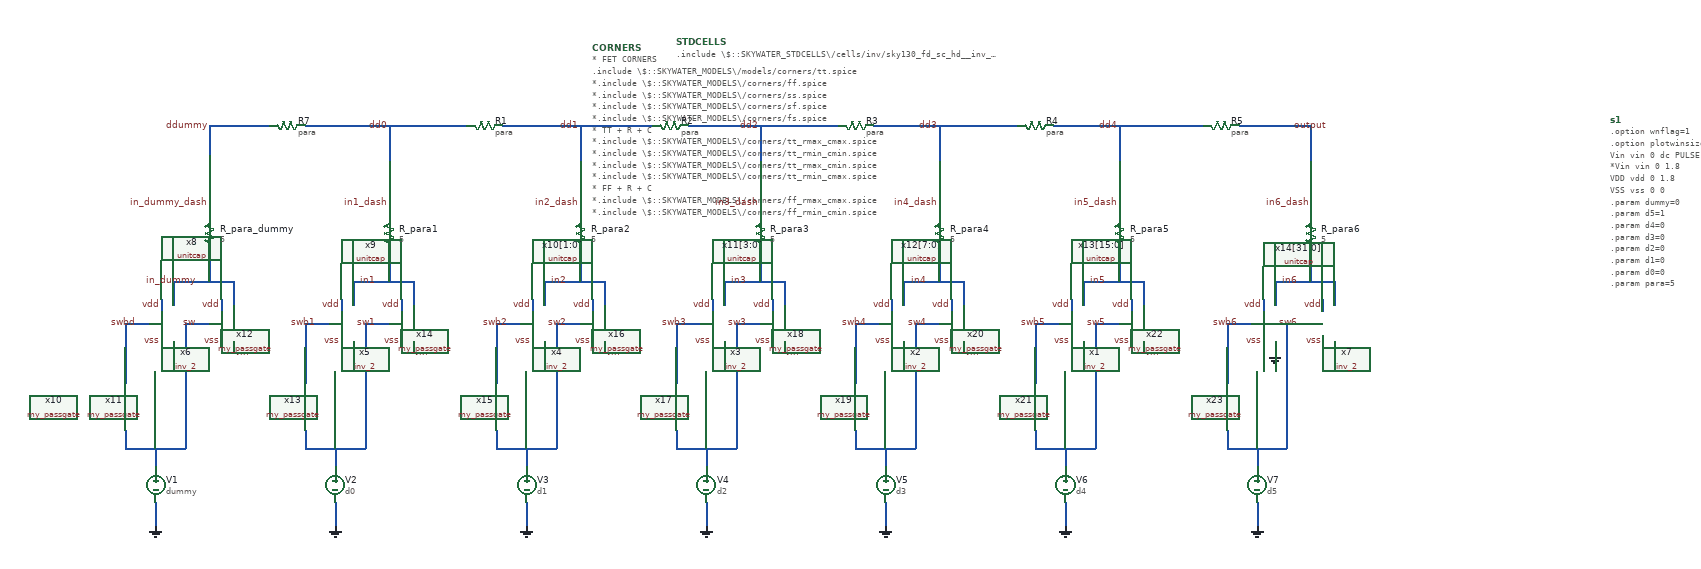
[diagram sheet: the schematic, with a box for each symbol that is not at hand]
v {xschem version=3.0.0 file_version=1.2 }
G {}
K {}
V {}
S {}
E {}
N 120 -60 120 -30 {
lab=sw}
N 120 -30 220 -30 {
lab=sw}
N 220 -170 220 -30 {
lab=sw}
N 120 -170 120 -140 {
lab=swbd}
N 200 -210 200 -190 {
lab=GND}
N 240 -240 260 -240 {
lab=sw}
N 140 -240 160 -240 {
lab=swbd}
N 220 -240 220 -170 {
lab=sw}
N 220 -240 240 -240 {
lab=sw}
N 120 -240 140 -240 {
lab=swbd}
N 120 -240 120 -170 {
lab=swbd}
N 300 -210 300 -190 {
lab=vin}
N 170 60 170 100 {
lab=GND}
N 170 -30 170 0 {
lab=sw}
N 200 -310 200 -270 {
lab=in_dummy}
N 200 -310 300 -310 {
lab=in_dummy}
N 300 -310 300 -270 {
lab=in_dummy}
N 420 -60 420 -30 {
lab=sw1}
N 420 -30 520 -30 {
lab=sw1}
N 520 -170 520 -30 {
lab=sw1}
N 420 -170 420 -140 {
lab=swb1}
N 500 -210 500 -190 {
lab=GND}
N 540 -240 560 -240 {
lab=sw1}
N 440 -240 460 -240 {
lab=swb1}
N 520 -240 520 -170 {
lab=sw1}
N 520 -240 540 -240 {
lab=sw1}
N 420 -240 440 -240 {
lab=swb1}
N 420 -240 420 -170 {
lab=swb1}
N 600 -210 600 -190 {
lab=vin}
N 470 60 470 100 {
lab=GND}
N 470 -30 470 0 {
lab=sw1}
N 500 -310 500 -270 {
lab=in1}
N 500 -310 600 -310 {
lab=in1}
N 600 -310 600 -270 {
lab=in1}
N 560 -450 560 -420 {
lab=in1_dash}
N 560 -570 560 -510 {
lab=d0}
N 740 -60 740 -30 {
lab=sw2}
N 740 -30 840 -30 {
lab=sw2}
N 840 -170 840 -30 {
lab=sw2}
N 740 -170 740 -140 {
lab=swb2}
N 820 -210 820 -190 {
lab=GND}
N 860 -240 880 -240 {
lab=sw2}
N 760 -240 780 -240 {
lab=swb2}
N 840 -240 840 -170 {
lab=sw2}
N 840 -240 860 -240 {
lab=sw2}
N 740 -240 760 -240 {
lab=swb2}
N 740 -240 740 -170 {
lab=swb2}
N 920 -210 920 -190 {
lab=vin}
N 790 60 790 100 {
lab=GND}
N 790 -30 790 0 {
lab=sw2}
N 820 -310 820 -270 {
lab=in2}
N 820 -310 920 -310 {
lab=in2}
N 920 -310 920 -270 {
lab=in2}
N 880 -450 880 -420 {
lab=in2_dash}
N 880 -570 880 -510 {
lab=dd1}
N 1040 -60 1040 -30 {
lab=sw3}
N 1040 -30 1140 -30 {
lab=sw3}
N 1140 -170 1140 -30 {
lab=sw3}
N 1040 -170 1040 -140 {
lab=swb3}
N 1120 -210 1120 -190 {
lab=GND}
N 1160 -240 1180 -240 {
lab=sw3}
N 1060 -240 1080 -240 {
lab=swb3}
N 1140 -240 1140 -170 {
lab=sw3}
N 1140 -240 1160 -240 {
lab=sw3}
N 1040 -240 1060 -240 {
lab=swb3}
N 1040 -240 1040 -170 {
lab=swb3}
N 1220 -210 1220 -190 {
lab=vin}
N 1090 60 1090 100 {
lab=GND}
N 1090 -30 1090 0 {
lab=sw3}
N 1120 -310 1120 -270 {
lab=in3}
N 1120 -310 1220 -310 {
lab=in3}
N 1220 -310 1220 -270 {
lab=in3}
N 1180 -450 1180 -420 {
lab=in3_dash}
N 1180 -570 1180 -510 {
lab=dd2}
N 1340 -60 1340 -30 {
lab=sw4}
N 1340 -30 1440 -30 {
lab=sw4}
N 1440 -170 1440 -30 {
lab=sw4}
N 1340 -170 1340 -140 {
lab=swb4}
N 1420 -210 1420 -190 {
lab=GND}
N 1460 -240 1480 -240 {
lab=sw4}
N 1360 -240 1380 -240 {
lab=swb4}
N 1440 -240 1440 -170 {
lab=sw4}
N 1440 -240 1460 -240 {
lab=sw4}
N 1340 -240 1360 -240 {
lab=swb4}
N 1340 -240 1340 -170 {
lab=swb4}
N 1520 -210 1520 -190 {
lab=vin}
N 1390 60 1390 100 {
lab=GND}
N 1390 -30 1390 0 {
lab=sw4}
N 1420 -310 1420 -270 {
lab=in4}
N 1420 -310 1520 -310 {
lab=in4}
N 1520 -310 1520 -270 {
lab=in4}
N 1480 -450 1480 -420 {
lab=in4_dash}
N 1480 -570 1480 -510 {
lab=dd3}
N 1640 -60 1640 -30 {
lab=sw5}
N 1640 -30 1740 -30 {
lab=sw5}
N 1740 -170 1740 -30 {
lab=sw5}
N 1640 -170 1640 -140 {
lab=swb5}
N 1720 -210 1720 -190 {
lab=GND}
N 1760 -240 1780 -240 {
lab=sw5}
N 1660 -240 1680 -240 {
lab=swb5}
N 1740 -240 1740 -170 {
lab=sw5}
N 1740 -240 1760 -240 {
lab=sw5}
N 1640 -240 1660 -240 {
lab=swb5}
N 1640 -240 1640 -170 {
lab=swb5}
N 1820 -210 1820 -190 {
lab=vin}
N 1690 60 1690 100 {
lab=GND}
N 1690 -30 1690 0 {
lab=sw5}
N 1720 -310 1720 -270 {
lab=in5}
N 1720 -310 1820 -310 {
lab=in5}
N 1820 -310 1820 -270 {
lab=in5}
N 1780 -450 1780 -420 {
lab=in5_dash}
N 1780 -570 1780 -510 {
lab=dd4}
N 1960 -60 1960 -30 {
lab=sw6}
N 1960 -30 2060 -30 {
lab=sw6}
N 2060 -170 2060 -30 {
lab=sw6}
N 1960 -170 1960 -140 {
lab=swb6}
N 2040 -210 2040 -190 {
lab=GND}
N 2080 -240 2100 -240 {
lab=sw6}
N 1980 -240 2000 -240 {
lab=swb6}
N 2060 -240 2060 -170 {
lab=sw6}
N 2060 -240 2080 -240 {
lab=sw6}
N 1960 -240 1980 -240 {
lab=swb6}
N 1960 -240 1960 -170 {
lab=swb6}
N 2140 -210 2140 -190 {
lab=vin}
N 2010 60 2010 100 {
lab=GND}
N 2010 -30 2010 0 {
lab=sw6}
N 2040 -310 2040 -270 {
lab=in6}
N 2040 -310 2140 -310 {
lab=in6}
N 2140 -310 2140 -270 {
lab=in6}
N 2100 -450 2100 -420 {
lab=in6_dash}
N 2100 -570 2100 -510 {
lab=output}
N 180 -220 180 -200 {
lab=vss}
N 180 -280 180 -260 {
lab=vdd}
N 280 -220 280 -200 {
lab=vss}
N 280 -280 280 -260 {
lab=vdd}
N 480 -220 480 -200 {
lab=vss}
N 480 -280 480 -260 {
lab=vdd}
N 580 -220 580 -200 {
lab=vss}
N 580 -280 580 -260 {
lab=vdd}
N 800 -220 800 -200 {
lab=vss}
N 800 -280 800 -260 {
lab=vdd}
N 900 -220 900 -200 {
lab=vss}
N 900 -280 900 -260 {
lab=vdd}
N 1100 -220 1100 -200 {
lab=vss}
N 1100 -280 1100 -260 {
lab=vdd}
N 1200 -220 1200 -200 {
lab=vss}
N 1200 -280 1200 -260 {
lab=vdd}
N 1400 -220 1400 -200 {
lab=vss}
N 1400 -280 1400 -260 {
lab=vdd}
N 1500 -220 1500 -200 {
lab=vss}
N 1500 -280 1500 -260 {
lab=vdd}
N 1700 -220 1700 -200 {
lab=vss}
N 1700 -280 1700 -260 {
lab=vdd}
N 1800 -220 1800 -200 {
lab=vss}
N 1800 -280 1800 -260 {
lab=vdd}
N 2020 -220 2020 -200 {
lab=vss}
N 2020 -280 2020 -260 {
lab=vdd}
N 2120 -220 2120 -200 {
lab=vss}
N 2120 -280 2120 -260 {
lab=vdd}
N 260 -570 260 -520 {
lab=ddummy}
N 260 -460 260 -420 {
lab=in_dummy_dash}
N 260 -570 360 -570 {
lab=ddummy}
N 420 -570 690 -570 {
lab=d0}
N 750 -570 1000 -570 {
lab=dd1}
N 1060 -570 1310 -570 {
lab=dd2}
N 1370 -570 1610 -570 {
lab=dd3}
N 1670 -570 1920 -570 {
lab=dd4}
N 1980 -570 2020 -570 {
lab=output}
N 2020 -570 2100 -570 {
lab=output}
N 260 -360 260 -310 {
lab=in_dummy}
N 560 -360 560 -310 {
lab=in1}
N 880 -360 880 -310 {
lab=in2}
N 1180 -360 1180 -310 {
lab=in3}
N 1480 -360 1480 -310 {
lab=in4}
N 1780 -360 1780 -310 {
lab=in5}
N 2100 -360 2100 -310 {
lab=in6}
C {gnd.sym} 200 -190 0 0 {name=l2 lab=GND}
C {lab_wire.sym} 240 -240 0 0 {name=l3 sig_type=std_logic lab=sw}
C {lab_wire.sym} 140 -240 0 0 {name=l4 sig_type=std_logic lab=swbd
}
C {vsource.sym} 170 30 0 0 {name=V1 value=dummy
}
C {gnd.sym} 170 100 0 0 {name=l7 lab=GND}
C {lab_wire.sym} 300 -190 2 0 {name=l6 sig_type=std_logic lab=vin
}
C {gnd.sym} 500 -190 0 0 {name=l9 lab=GND}
C {lab_wire.sym} 540 -240 0 0 {name=l10 sig_type=std_logic lab=sw1}
C {lab_wire.sym} 440 -240 0 0 {name=l11 sig_type=std_logic lab=swb1
}
C {vsource.sym} 470 30 0 0 {name=V2 value=d0}
C {gnd.sym} 470 100 0 0 {name=l13 lab=GND}
C {lab_wire.sym} 600 -190 2 0 {name=l14 sig_type=std_logic lab=vin
}
C {gnd.sym} 820 -190 0 0 {name=l16 lab=GND}
C {lab_wire.sym} 860 -240 0 0 {name=l17 sig_type=std_logic lab=sw2}
C {lab_wire.sym} 760 -240 0 0 {name=l18 sig_type=std_logic lab=swb2
}
C {vsource.sym} 790 30 0 0 {name=V3 value=d1
}
C {gnd.sym} 790 100 0 0 {name=l20 lab=GND}
C {lab_wire.sym} 920 -190 2 0 {name=l21 sig_type=std_logic lab=vin
}
C {gnd.sym} 1120 -190 0 0 {name=l23 lab=GND}
C {lab_wire.sym} 1160 -240 0 0 {name=l24 sig_type=std_logic lab=sw3}
C {lab_wire.sym} 1060 -240 0 0 {name=l25 sig_type=std_logic lab=swb3
}
C {vsource.sym} 1090 30 0 0 {name=V4 value=d2}
C {gnd.sym} 1090 100 0 0 {name=l27 lab=GND}
C {lab_wire.sym} 1220 -190 2 0 {name=l28 sig_type=std_logic lab=vin
}
C {gnd.sym} 1420 -190 0 0 {name=l30 lab=GND}
C {lab_wire.sym} 1460 -240 0 0 {name=l31 sig_type=std_logic lab=sw4}
C {lab_wire.sym} 1360 -240 0 0 {name=l32 sig_type=std_logic lab=swb4
}
C {vsource.sym} 1390 30 0 0 {name=V5 value=d3
}
C {gnd.sym} 1390 100 0 0 {name=l34 lab=GND}
C {lab_wire.sym} 1520 -190 2 0 {name=l35 sig_type=std_logic lab=vin
}
C {gnd.sym} 1720 -190 0 0 {name=l37 lab=GND}
C {lab_wire.sym} 1760 -240 0 0 {name=l38 sig_type=std_logic lab=sw5}
C {lab_wire.sym} 1660 -240 0 0 {name=l39 sig_type=std_logic lab=swb5
}
C {vsource.sym} 1690 30 0 0 {name=V6 value=d4
}
C {gnd.sym} 1690 100 0 0 {name=l41 lab=GND}
C {lab_wire.sym} 1820 -190 2 0 {name=l42 sig_type=std_logic lab=vin
}
C {gnd.sym} 2040 -190 0 0 {name=l44 lab=GND}
C {lab_wire.sym} 2080 -240 0 0 {name=l45 sig_type=std_logic lab=sw6}
C {lab_wire.sym} 1980 -240 0 0 {name=l46 sig_type=std_logic lab=swb6
}
C {vsource.sym} 2010 30 0 0 {name=V7 value=d5
}
C {gnd.sym} 2010 100 0 0 {name=l48 lab=GND}
C {lab_wire.sym} 2140 -190 2 0 {name=l49 sig_type=std_logic lab=vin
}
C {devices/code.sym} 900 -700 0 0 {
name=CORNERS 
only_toplevel=true 
format="tcleval( @value )"
spice_ignore="tcleval($cmdline_ignore)"
value="* FET CORNERS
.include \\\\$::SKYWATER_MODELS\\\\/models/corners/tt.spice
*.include \\\\$::SKYWATER_MODELS\\\\/corners/ff.spice
*.include \\\\$::SKYWATER_MODELS\\\\/corners/ss.spice
*.include \\\\$::SKYWATER_MODELS\\\\/corners/sf.spice
*.include \\\\$::SKYWATER_MODELS\\\\/corners/fs.spice

* TT + R + C
*.include \\\\$::SKYWATER_MODELS\\\\/corners/tt_rmax_cmax.spice
*.include \\\\$::SKYWATER_MODELS\\\\/corners/tt_rmin_cmin.spice
*.include \\\\$::SKYWATER_MODELS\\\\/corners/tt_rmax_cmin.spice
*.include \\\\$::SKYWATER_MODELS\\\\/corners/tt_rmin_cmax.spice

* FF + R + C
*.include \\\\$::SKYWATER_MODELS\\\\/corners/ff_rmax_cmax.spice
*.include \\\\$::SKYWATER_MODELS\\\\/corners/ff_rmin_cmin.spice
*.include \\\\$::SKYWATER_MODELS\\\\/corners/ff_rmax_cmin.spice
*.include \\\\$::SKYWATER_MODELS\\\\/corners/ff_rmin_cmax.spice


* SS + R + C
*.include \\\\$::SKYWATER_MODELS\\\\/corners/ss_rmax_cmax.spice
*.include \\\\$::SKYWATER_MODELS\\\\/corners/ss_rmin_cmin.spice
*.include \\\\$::SKYWATER_MODELS\\\\/corners/ss_rmax_cmin.spice
*.include \\\\$::SKYWATER_MODELS\\\\/corners/ss_rmin_cmax.spice

* SF + R + C
*.include \\\\$::SKYWATER_MODELS\\\\/corners/sf_rmax_cmax.spice
*.include \\\\$::SKYWATER_MODELS\\\\/corners/sf_rmin_cmin.spice
*.include \\\\$::SKYWATER_MODELS\\\\/corners/sf_rmax_cmin.spice
*.include \\\\$::SKYWATER_MODELS\\\\/corners/sf_rmin_cmax.spice

* FS + R + C
*.include \\\\$::SKYWATER_MODELS\\\\/corners/fs_rmax_cmax.spice
*.include \\\\$::SKYWATER_MODELS\\\\/corners/fs_rmin_cmin.spice
*.include \\\\$::SKYWATER_MODELS\\\\/corners/fs_rmax_cmin.spice
*.include \\\\$::SKYWATER_MODELS\\\\/corners/fs_rmin_cmax.spice
"}
C {code_shown.sym} 2600 -580 0 0 {name=s1 only_toplevel=false value="
.option wnflag=1
.option plotwinsize=0
Vin vin 0 dc PULSE(0 1 0 12.8u 0 0.2u 13u)
*Vin vin 0 1.8
VDD vdd 0 1.8
VSS vss 0 0

.param dummy=0
.param d5=1
.param d4=0
.param d3=0
.param d2=0
.param d1=0
.param d0=0
.param para=5

.control
save all
tran 1u 13u

meas tran output find v(d5) at=13u

wrdata out output
print output
.endc
"}
C {devices/code.sym} 1040 -710 0 0 {
name=STDCELLS 
only_toplevel=false 
format="tcleval( @value )"
value="

.include \\\\$::SKYWATER_STDCELLS\\\\/cells/inv/sky130_fd_sc_hd__inv_2.spice"
}
C {sar_10b/unitcap/unitcap.sym} 540 -440 0 0 {name=x9}
C {sar_10b/unitcap/unitcap.sym} 860 -440 0 0 {name=x10[1:0]}
C {sar_10b/unitcap/unitcap.sym} 1160 -440 0 0 {name=x11[3:0]}
C {sar_10b/unitcap/unitcap.sym} 1460 -440 0 0 {name=x12[7:0]}
C {sar_10b/unitcap/unitcap.sym} 1760 -440 0 0 {name=x13[15:0]}
C {sar_10b/unitcap/unitcap.sym} 2080 -440 0 0 {name=x14[31:0]}
C {switches/my_passgate.sym} 0 -100 0 0 {name=x10}
C {lab_wire.sym} 180 -210 0 0 {name=l1 sig_type=std_logic lab=vss}
C {lab_wire.sym} 180 -270 0 0 {name=l51 sig_type=std_logic lab=vdd}
C {switches/my_passgate.sym} 100 -100 0 0 {name=x11}
C {lab_wire.sym} 280 -210 0 0 {name=l5 sig_type=std_logic lab=vss}
C {lab_wire.sym} 280 -270 0 0 {name=l8 sig_type=std_logic lab=vdd}
C {switches/my_passgate.sym} 300 -100 0 0 {name=x12}
C {lab_wire.sym} 480 -210 0 0 {name=l12 sig_type=std_logic lab=vss}
C {lab_wire.sym} 480 -270 0 0 {name=l15 sig_type=std_logic lab=vdd}
C {switches/my_passgate.sym} 400 -100 0 0 {name=x13}
C {lab_wire.sym} 580 -210 0 0 {name=l19 sig_type=std_logic lab=vss}
C {lab_wire.sym} 580 -270 0 0 {name=l22 sig_type=std_logic lab=vdd}
C {switches/my_passgate.sym} 620 -100 0 0 {name=x14}
C {lab_wire.sym} 800 -210 0 0 {name=l26 sig_type=std_logic lab=vss}
C {lab_wire.sym} 800 -270 0 0 {name=l29 sig_type=std_logic lab=vdd}
C {switches/my_passgate.sym} 720 -100 0 0 {name=x15}
C {lab_wire.sym} 900 -210 0 0 {name=l33 sig_type=std_logic lab=vss}
C {lab_wire.sym} 900 -270 0 0 {name=l36 sig_type=std_logic lab=vdd}
C {switches/my_passgate.sym} 920 -100 0 0 {name=x16}
C {lab_wire.sym} 1100 -210 0 0 {name=l40 sig_type=std_logic lab=vss}
C {lab_wire.sym} 1100 -270 0 0 {name=l43 sig_type=std_logic lab=vdd}
C {switches/my_passgate.sym} 1020 -100 0 0 {name=x17}
C {lab_wire.sym} 1200 -210 0 0 {name=l47 sig_type=std_logic lab=vss}
C {lab_wire.sym} 1200 -270 0 0 {name=l52 sig_type=std_logic lab=vdd}
C {switches/my_passgate.sym} 1220 -100 0 0 {name=x18}
C {lab_wire.sym} 1400 -210 0 0 {name=l53 sig_type=std_logic lab=vss}
C {lab_wire.sym} 1400 -270 0 0 {name=l54 sig_type=std_logic lab=vdd}
C {switches/my_passgate.sym} 1320 -100 0 0 {name=x19}
C {lab_wire.sym} 1500 -210 0 0 {name=l55 sig_type=std_logic lab=vss}
C {lab_wire.sym} 1500 -270 0 0 {name=l56 sig_type=std_logic lab=vdd}
C {switches/my_passgate.sym} 1520 -100 0 0 {name=x20}
C {lab_wire.sym} 1700 -210 0 0 {name=l57 sig_type=std_logic lab=vss}
C {lab_wire.sym} 1700 -270 0 0 {name=l58 sig_type=std_logic lab=vdd}
C {switches/my_passgate.sym} 1620 -100 0 0 {name=x21}
C {lab_wire.sym} 1800 -210 0 0 {name=l59 sig_type=std_logic lab=vss}
C {lab_wire.sym} 1800 -270 0 0 {name=l60 sig_type=std_logic lab=vdd}
C {switches/my_passgate.sym} 1840 -100 0 0 {name=x22}
C {lab_wire.sym} 2020 -210 0 0 {name=l61 sig_type=std_logic lab=vss}
C {lab_wire.sym} 2020 -270 0 0 {name=l62 sig_type=std_logic lab=vdd}
C {switches/my_passgate.sym} 1940 -100 0 0 {name=x23}
C {lab_wire.sym} 2120 -210 0 0 {name=l63 sig_type=std_logic lab=vss}
C {lab_wire.sym} 2120 -270 0 0 {name=l64 sig_type=std_logic lab=vdd}
C {lab_wire.sym} 2070 -570 0 1 {name=l65 sig_type=std_logic lab=output}
C {xschem_sky130/sky130_stdcells/inv_2.sym} 1960 -100 3 0 {name=x7 VGND=vss VNB=vss VPB=vdd VPWR=vdd prefix=sky130_fd_sc_hd__ }
C {xschem_sky130/sky130_stdcells/inv_2.sym} 1640 -100 3 0 {name=x1 VGND=vss VNB=vss VPB=vdd VPWR=vdd prefix=sky130_fd_sc_hd__ }
C {xschem_sky130/sky130_stdcells/inv_2.sym} 1340 -100 3 0 {name=x2 VGND=vss VNB=vss VPB=vdd VPWR=vdd prefix=sky130_fd_sc_hd__ }
C {xschem_sky130/sky130_stdcells/inv_2.sym} 1040 -100 3 0 {name=x3 VGND=vss VNB=vss VPB=vdd VPWR=vdd prefix=sky130_fd_sc_hd__ }
C {xschem_sky130/sky130_stdcells/inv_2.sym} 740 -100 3 0 {name=x4 VGND=vss VNB=vss VPB=vdd VPWR=vdd prefix=sky130_fd_sc_hd__ }
C {xschem_sky130/sky130_stdcells/inv_2.sym} 420 -100 3 0 {name=x5 VGND=vss VNB=vss VPB=vdd VPWR=vdd prefix=sky130_fd_sc_hd__ }
C {xschem_sky130/sky130_stdcells/inv_2.sym} 120 -100 3 0 {name=x6 VGND=vss VNB=vss VPB=vdd VPWR=vdd prefix=sky130_fd_sc_hd__ }
C {sar_10b/unitcap/unitcap.sym} 240 -450 0 0 {name=x8}
C {res.sym} 390 -570 1 0 {name=R7
value=para
footprint=1206
device=resistor
m=1}
C {res.sym} 720 -570 1 0 {name=R1
value=para
footprint=1206
device=resistor
m=1}
C {res.sym} 1030 -570 1 0 {name=R2
value=para
footprint=1206
device=resistor
m=1}
C {res.sym} 1340 -570 1 0 {name=R3
value=para
footprint=1206
device=resistor
m=1}
C {res.sym} 1640 -570 1 0 {name=R4
value=para
footprint=1206
device=resistor
m=1}
C {res.sym} 1950 -570 1 0 {name=R5
value=para
footprint=1206
device=resistor
m=1}
C {lab_wire.sym} 540 -310 0 0 {name=l66 sig_type=std_logic lab=in1}
C {lab_wire.sym} 860 -310 0 0 {name=l67 sig_type=std_logic lab=in2}
C {lab_wire.sym} 1160 -310 0 0 {name=l68 sig_type=std_logic lab=in3}
C {lab_wire.sym} 1460 -310 0 0 {name=l69 sig_type=std_logic lab=in4}
C {lab_wire.sym} 1760 -310 0 0 {name=l70 sig_type=std_logic lab=in5}
C {lab_wire.sym} 2080 -310 0 0 {name=l71 sig_type=std_logic lab=in6}
C {lab_wire.sym} 240 -310 0 0 {name=l72 sig_type=std_logic lab=in_dummy}
C {lab_wire.sym} 260 -570 0 0 {name=l50 sig_type=std_logic lab=ddummy}
C {lab_wire.sym} 560 -570 0 0 {name=l73 sig_type=std_logic lab=dd0}
C {lab_wire.sym} 880 -570 0 0 {name=l74 sig_type=std_logic lab=dd1}
C {lab_wire.sym} 1180 -570 0 0 {name=l75 sig_type=std_logic lab=dd2}
C {lab_wire.sym} 1480 -570 0 0 {name=l76 sig_type=std_logic lab=dd3}
C {lab_wire.sym} 1780 -570 0 0 {name=l77 sig_type=std_logic lab=dd4}
C {res.sym} 260 -390 2 0 {name=R_para_dummy
value=5
footprint=1206
device=resistor
m=1}
C {lab_wire.sym} 260 -440 0 0 {name=l78 sig_type=std_logic lab=in_dummy_dash}
C {res.sym} 560 -390 2 0 {name=R_para1
value=5
footprint=1206
device=resistor
m=1}
C {lab_wire.sym} 560 -440 0 0 {name=l79 sig_type=std_logic lab=in1_dash}
C {res.sym} 880 -390 2 0 {name=R_para2
value=5
footprint=1206
device=resistor
m=1}
C {lab_wire.sym} 880 -440 0 0 {name=l80 sig_type=std_logic lab=in2_dash}
C {res.sym} 1180 -390 2 0 {name=R_para3
value=5
footprint=1206
device=resistor
m=1}
C {lab_wire.sym} 1180 -440 0 0 {name=l81 sig_type=std_logic lab=in3_dash}
C {res.sym} 1480 -390 2 0 {name=R_para4
value=5
footprint=1206
device=resistor
m=1}
C {lab_wire.sym} 1480 -440 0 0 {name=l82 sig_type=std_logic lab=in4_dash}
C {res.sym} 1780 -390 2 0 {name=R_para5
value=5
footprint=1206
device=resistor
m=1}
C {lab_wire.sym} 1780 -440 0 0 {name=l83 sig_type=std_logic lab=in5_dash}
C {res.sym} 2100 -390 2 0 {name=R_para6
value=5
footprint=1206
device=resistor
m=1}
C {lab_wire.sym} 2100 -440 0 0 {name=l84 sig_type=std_logic lab=in6_dash}
